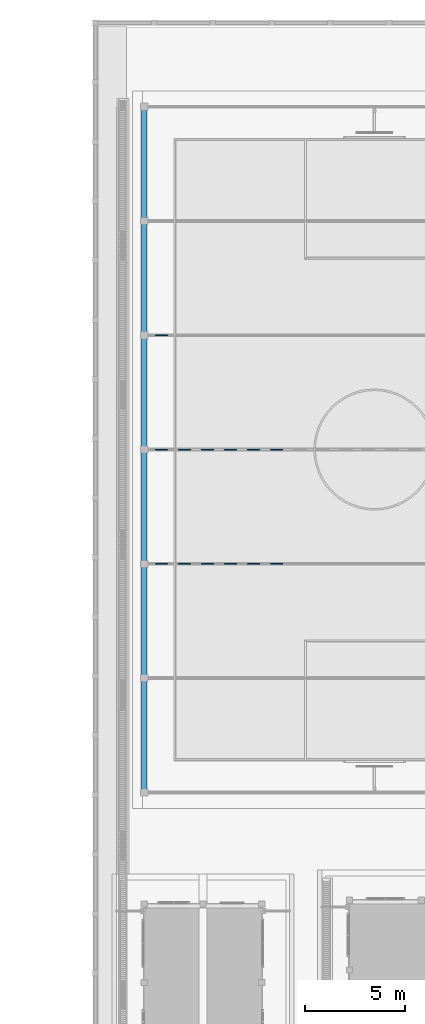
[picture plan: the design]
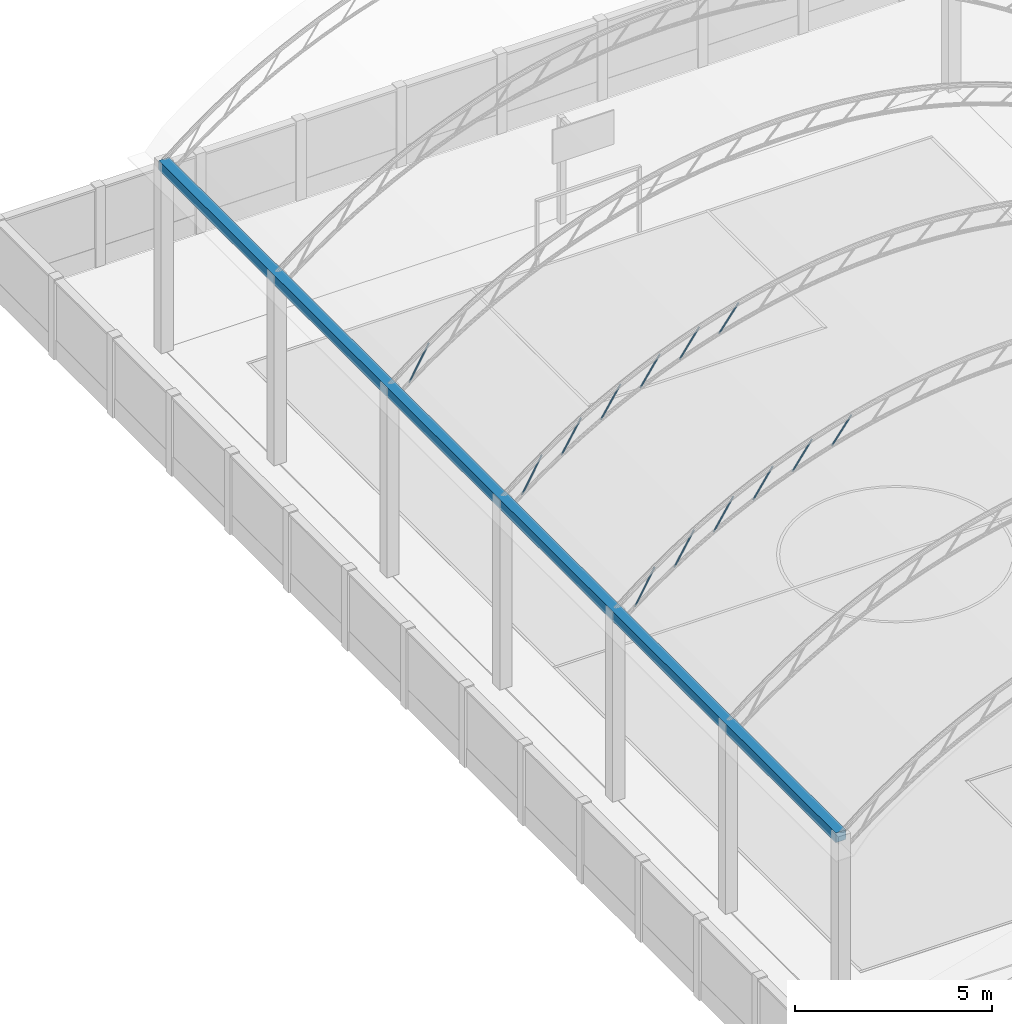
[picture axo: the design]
# One storey, part 19 of 166: 14 beams.
"""IFC2X3 building model written with IfcOpenShell, lengths in metres."""

from ifc_helpers import new_model, si_unit, origin, origin_with_axes, place, context, subcontext, project, spatial, faceted_brep, element, save


model = new_model("IFC2X3")

# Units and contexts
model_context = context("Model", 3, precision=1e-05, world=origin_with_axes())
body_context = subcontext(model_context, "Body", "Model", "MODEL_VIEW")
ifc_project = project(units=[si_unit("LENGTHUNIT", "METRE"), si_unit("AREAUNIT", "SQUARE_METRE"), si_unit("VOLUMEUNIT", "CUBIC_METRE"), si_unit("PLANEANGLEUNIT", "RADIAN")], contexts=[model_context])

# Site, building, storey
site_placement = place(None, origin_with_axes())
site = spatial("IfcSite", under=ifc_project, at=site_placement, CompositionType="ELEMENT")
building_placement = place(site_placement, origin())
building = spatial("IfcBuilding", under=site, at=building_placement, Name="de Temporal", CompositionType="ELEMENT")
storey_placement = place(building_placement, origin())
storey = spatial("IfcBuildingStorey", under=building, at=storey_placement, Name="NIVEL 1 (NPT +0.00)", CompositionType="ELEMENT", Elevation=0.0)

# Beams
beam_1_placement = place(storey_placement, origin())
element("IfcBeam", 1, at=beam_1_placement, inside=storey, Name="diag", ObjectType="Viga", context=body_context, shape_type="Brep", body=[
    faceted_brep([(4.0666, 104.0883, 5.8202), (4.6441, 104.0883, 6.8469), (4.655, 104.0917, 6.8408), (4.0775, 104.0917, 5.8141), (4.0586, 104.0792, 5.8247), (4.6361, 104.0792, 6.8514), (4.0557, 104.0667, 5.8263), (4.6332, 104.0667, 6.8531), (4.0586, 104.0542, 5.8247), (4.6361, 104.0542, 6.8514), (4.0666, 104.045, 5.8202), (4.6441, 104.045, 6.8469), (4.0775, 104.0417, 5.8141), (4.655, 104.0417, 6.8408), (4.0884, 104.045, 5.808), (4.6659, 104.045, 6.8347), (4.0964, 104.0542, 5.8035), (4.6739, 104.0542, 6.8302), (4.0993, 104.0667, 5.8018), (4.6768, 104.0667, 6.8286), (4.0964, 104.0792, 5.8035), (4.6739, 104.0792, 6.8302), (4.0884, 104.0883, 5.808), (4.6659, 104.0883, 6.8347), (4.0756, 104.0704, 5.8151), (4.0775, 104.071, 5.8141), (4.655, 104.071, 6.8408), (4.6531, 104.0704, 6.8419), (4.0743, 104.0688, 5.8159), (4.6518, 104.0688, 6.8426), (4.0738, 104.0667, 5.8162), (4.6513, 104.0667, 6.8429), (4.0743, 104.0645, 5.8159), (4.6518, 104.0645, 6.8426), (4.0756, 104.0629, 5.8151), (4.6531, 104.0629, 6.8419), (4.0775, 104.0624, 5.8141), (4.655, 104.0624, 6.8408), (4.0794, 104.0629, 5.813), (4.6569, 104.0629, 6.8398), (4.0807, 104.0645, 5.8123), (4.6582, 104.0645, 6.839), (4.0812, 104.0667, 5.812), (4.6587, 104.0667, 6.8387), (4.0807, 104.0688, 5.8123), (4.6582, 104.0688, 6.839), (4.0794, 104.0704, 5.813), (4.6569, 104.0704, 6.8398)], [[[0, 1, 2, 3]], [[4, 5, 1, 0]], [[6, 7, 5, 4]], [[8, 9, 7, 6]], [[10, 11, 9, 8]], [[12, 13, 11, 10]], [[14, 15, 13, 12]], [[16, 17, 15, 14]], [[18, 19, 17, 16]], [[20, 21, 19, 18]], [[22, 23, 21, 20]], [[3, 2, 23, 22]], [[24, 25, 26, 27]], [[28, 24, 27, 29]], [[30, 28, 29, 31]], [[32, 30, 31, 33]], [[34, 32, 33, 35]], [[36, 34, 35, 37]], [[38, 36, 37, 39]], [[40, 38, 39, 41]], [[42, 40, 41, 43]], [[44, 42, 43, 45]], [[46, 44, 45, 47]], [[25, 46, 47, 26]], [[3, 22, 46, 25]], [[7, 9, 33, 31]], [[17, 19, 43, 41]], [[23, 2, 26, 47]], [[10, 8, 32, 34]], [[20, 18, 42, 44]], [[1, 5, 29, 27]], [[13, 15, 39, 37]], [[6, 4, 28, 30]], [[16, 14, 38, 40]], [[0, 3, 25, 24]], [[9, 11, 35, 33]], [[19, 21, 45, 43]], [[12, 10, 34, 36]], [[22, 20, 44, 46]], [[5, 7, 31, 29]], [[15, 17, 41, 39]], [[2, 1, 27, 26]], [[8, 6, 30, 32]], [[18, 16, 40, 42]], [[11, 13, 37, 35]], [[21, 23, 47, 45]], [[4, 0, 24, 28]], [[14, 12, 36, 38]]]),
])
beam_2_placement = place(storey_placement, origin())
element("IfcBeam", 2, at=beam_2_placement, inside=storey, Name="diag", ObjectType="Viga", context=body_context, shape_type="Brep", body=[
    faceted_brep([(5.2218, 104.0883, 6.6398), (5.7993, 104.0883, 7.6007), (5.81, 104.0917, 7.5943), (5.2325, 104.0917, 6.6333), (5.2139, 104.0792, 6.6445), (5.7914, 104.0792, 7.6055), (5.2111, 104.0667, 6.6462), (5.7886, 104.0667, 7.6072), (5.2139, 104.0542, 6.6445), (5.7914, 104.0542, 7.6055), (5.2218, 104.045, 6.6398), (5.7993, 104.045, 7.6007), (5.2325, 104.0417, 6.6333), (5.81, 104.0417, 7.5943), (5.2432, 104.045, 6.6269), (5.8207, 104.045, 7.5879), (5.2511, 104.0542, 6.6222), (5.8286, 104.0542, 7.5832), (5.2539, 104.0667, 6.6205), (5.8314, 104.0667, 7.5814), (5.2511, 104.0792, 6.6222), (5.8286, 104.0792, 7.5832), (5.2432, 104.0883, 6.6269), (5.8207, 104.0883, 7.5879), (5.2307, 104.0704, 6.6345), (5.2325, 104.071, 6.6333), (5.81, 104.071, 7.5943), (5.8082, 104.0704, 7.5954), (5.2293, 104.0688, 6.6353), (5.8068, 104.0688, 7.5962), (5.2288, 104.0667, 6.6356), (5.8063, 104.0667, 7.5965), (5.2293, 104.0645, 6.6353), (5.8068, 104.0645, 7.5962), (5.2307, 104.0629, 6.6345), (5.8082, 104.0629, 7.5954), (5.2325, 104.0624, 6.6333), (5.81, 104.0624, 7.5943), (5.2343, 104.0629, 6.6322), (5.8118, 104.0629, 7.5932), (5.2357, 104.0645, 6.6314), (5.8132, 104.0645, 7.5924), (5.2362, 104.0667, 6.6311), (5.8137, 104.0667, 7.5921), (5.2357, 104.0688, 6.6314), (5.8132, 104.0688, 7.5924), (5.2343, 104.0704, 6.6322), (5.8118, 104.0704, 7.5932)], [[[0, 1, 2, 3]], [[4, 5, 1, 0]], [[6, 7, 5, 4]], [[8, 9, 7, 6]], [[10, 11, 9, 8]], [[12, 13, 11, 10]], [[14, 15, 13, 12]], [[16, 17, 15, 14]], [[18, 19, 17, 16]], [[20, 21, 19, 18]], [[22, 23, 21, 20]], [[3, 2, 23, 22]], [[24, 25, 26, 27]], [[28, 24, 27, 29]], [[30, 28, 29, 31]], [[32, 30, 31, 33]], [[34, 32, 33, 35]], [[36, 34, 35, 37]], [[38, 36, 37, 39]], [[40, 38, 39, 41]], [[42, 40, 41, 43]], [[44, 42, 43, 45]], [[46, 44, 45, 47]], [[25, 46, 47, 26]], [[3, 22, 46, 25]], [[7, 9, 33, 31]], [[17, 19, 43, 41]], [[23, 2, 26, 47]], [[10, 8, 32, 34]], [[20, 18, 42, 44]], [[1, 5, 29, 27]], [[13, 15, 39, 37]], [[6, 4, 28, 30]], [[16, 14, 38, 40]], [[0, 3, 25, 24]], [[9, 11, 35, 33]], [[19, 21, 45, 43]], [[12, 10, 34, 36]], [[22, 20, 44, 46]], [[5, 7, 31, 29]], [[15, 17, 41, 39]], [[2, 1, 27, 26]], [[8, 6, 30, 32]], [[18, 16, 40, 42]], [[11, 13, 37, 35]], [[21, 23, 47, 45]], [[4, 0, 24, 28]], [[14, 12, 36, 38]]]),
])
beam_3_placement = place(storey_placement, origin())
element("IfcBeam", 3, at=beam_3_placement, inside=storey, Name="diag", ObjectType="Viga", context=body_context, shape_type="Brep", body=[
    faceted_brep([(6.377, 104.0883, 7.3326), (6.9545, 104.0883, 8.2366), (6.965, 104.0917, 8.2298), (6.3875, 104.0917, 7.3259), (6.3693, 104.0792, 7.3375), (6.9468, 104.0792, 8.2415), (6.3664, 104.0667, 7.3393), (6.9439, 104.0667, 8.2433), (6.3693, 104.0542, 7.3375), (6.9468, 104.0542, 8.2415), (6.377, 104.045, 7.3326), (6.9545, 104.045, 8.2366), (6.3875, 104.0417, 7.3259), (6.965, 104.0417, 8.2298), (6.398, 104.045, 7.3191), (6.9755, 104.045, 8.2231), (6.4057, 104.0542, 7.3142), (6.9832, 104.0542, 8.2182), (6.4086, 104.0667, 7.3124), (6.9861, 104.0667, 8.2164), (6.4057, 104.0792, 7.3142), (6.9832, 104.0792, 8.2182), (6.398, 104.0883, 7.3191), (6.9755, 104.0883, 8.2231), (6.3857, 104.0704, 7.327), (6.3875, 104.071, 7.3259), (6.965, 104.071, 8.2298), (6.9632, 104.0704, 8.231), (6.3844, 104.0688, 7.3279), (6.9619, 104.0688, 8.2318), (6.3839, 104.0667, 7.3282), (6.9614, 104.0667, 8.2321), (6.3844, 104.0645, 7.3279), (6.9619, 104.0645, 8.2318), (6.3857, 104.0629, 7.327), (6.9632, 104.0629, 8.231), (6.3875, 104.0624, 7.3259), (6.965, 104.0624, 8.2298), (6.3893, 104.0629, 7.3247), (6.9668, 104.0629, 8.2287), (6.3906, 104.0645, 7.3239), (6.9681, 104.0645, 8.2278), (6.3911, 104.0667, 7.3235), (6.9686, 104.0667, 8.2275), (6.3906, 104.0688, 7.3239), (6.9681, 104.0688, 8.2278), (6.3893, 104.0704, 7.3247), (6.9668, 104.0704, 8.2287)], [[[0, 1, 2, 3]], [[4, 5, 1, 0]], [[6, 7, 5, 4]], [[8, 9, 7, 6]], [[10, 11, 9, 8]], [[12, 13, 11, 10]], [[14, 15, 13, 12]], [[16, 17, 15, 14]], [[18, 19, 17, 16]], [[20, 21, 19, 18]], [[22, 23, 21, 20]], [[3, 2, 23, 22]], [[24, 25, 26, 27]], [[28, 24, 27, 29]], [[30, 28, 29, 31]], [[32, 30, 31, 33]], [[34, 32, 33, 35]], [[36, 34, 35, 37]], [[38, 36, 37, 39]], [[40, 38, 39, 41]], [[42, 40, 41, 43]], [[44, 42, 43, 45]], [[46, 44, 45, 47]], [[25, 46, 47, 26]], [[3, 22, 46, 25]], [[7, 9, 33, 31]], [[17, 19, 43, 41]], [[23, 2, 26, 47]], [[10, 8, 32, 34]], [[20, 18, 42, 44]], [[1, 5, 29, 27]], [[13, 15, 39, 37]], [[6, 4, 28, 30]], [[16, 14, 38, 40]], [[0, 3, 25, 24]], [[9, 11, 35, 33]], [[19, 21, 45, 43]], [[12, 10, 34, 36]], [[22, 20, 44, 46]], [[5, 7, 31, 29]], [[15, 17, 41, 39]], [[2, 1, 27, 26]], [[8, 6, 30, 32]], [[18, 16, 40, 42]], [[11, 13, 37, 35]], [[21, 23, 47, 45]], [[4, 0, 24, 28]], [[14, 12, 36, 38]]]),
])
beam_4_placement = place(storey_placement, origin())
element("IfcBeam", 4, at=beam_4_placement, inside=storey, Name="diag", ObjectType="Viga", context=body_context, shape_type="Brep", body=[
    faceted_brep([(7.5321, 104.0883, 7.9148), (8.1096, 104.0883, 8.7679), (8.12, 104.0917, 8.7609), (7.5425, 104.0917, 7.9077), (7.5246, 104.0792, 7.9199), (8.1021, 104.0792, 8.7731), (7.5218, 104.0667, 7.9218), (8.0993, 104.0667, 8.7749), (7.5246, 104.0542, 7.9199), (8.1021, 104.0542, 8.7731), (7.5321, 104.045, 7.9148), (8.1096, 104.045, 8.7679), (7.5425, 104.0417, 7.9077), (8.12, 104.0417, 8.7609), (7.5529, 104.045, 7.9007), (8.1304, 104.045, 8.7539), (7.5604, 104.0542, 7.8956), (8.1379, 104.0542, 8.7488), (7.5632, 104.0667, 7.8937), (8.1407, 104.0667, 8.7469), (7.5604, 104.0792, 7.8956), (8.1379, 104.0792, 8.7488), (7.5529, 104.0883, 7.9007), (8.1304, 104.0883, 8.7539), (7.5407, 104.0704, 7.9089), (7.5425, 104.071, 7.9077), (8.12, 104.071, 8.7609), (8.1182, 104.0704, 8.7621), (7.5394, 104.0688, 7.9098), (8.1169, 104.0688, 8.763), (7.5389, 104.0667, 7.9102), (8.1164, 104.0667, 8.7633), (7.5394, 104.0645, 7.9098), (8.1169, 104.0645, 8.763), (7.5407, 104.0629, 7.9089), (8.1182, 104.0629, 8.7621), (7.5425, 104.0624, 7.9077), (8.12, 104.0624, 8.7609), (7.5443, 104.0629, 7.9065), (8.1218, 104.0629, 8.7597), (7.5456, 104.0645, 7.9057), (8.1231, 104.0645, 8.7588), (7.5461, 104.0667, 7.9053), (8.1236, 104.0667, 8.7585), (7.5456, 104.0688, 7.9057), (8.1231, 104.0688, 8.7588), (7.5443, 104.0704, 7.9065), (8.1218, 104.0704, 8.7597)], [[[0, 1, 2, 3]], [[4, 5, 1, 0]], [[6, 7, 5, 4]], [[8, 9, 7, 6]], [[10, 11, 9, 8]], [[12, 13, 11, 10]], [[14, 15, 13, 12]], [[16, 17, 15, 14]], [[18, 19, 17, 16]], [[20, 21, 19, 18]], [[22, 23, 21, 20]], [[3, 2, 23, 22]], [[24, 25, 26, 27]], [[28, 24, 27, 29]], [[30, 28, 29, 31]], [[32, 30, 31, 33]], [[34, 32, 33, 35]], [[36, 34, 35, 37]], [[38, 36, 37, 39]], [[40, 38, 39, 41]], [[42, 40, 41, 43]], [[44, 42, 43, 45]], [[46, 44, 45, 47]], [[25, 46, 47, 26]], [[3, 22, 46, 25]], [[7, 9, 33, 31]], [[17, 19, 43, 41]], [[23, 2, 26, 47]], [[10, 8, 32, 34]], [[20, 18, 42, 44]], [[1, 5, 29, 27]], [[13, 15, 39, 37]], [[6, 4, 28, 30]], [[16, 14, 38, 40]], [[0, 3, 25, 24]], [[9, 11, 35, 33]], [[19, 21, 45, 43]], [[12, 10, 34, 36]], [[22, 20, 44, 46]], [[5, 7, 31, 29]], [[15, 17, 41, 39]], [[2, 1, 27, 26]], [[8, 6, 30, 32]], [[18, 16, 40, 42]], [[11, 13, 37, 35]], [[21, 23, 47, 45]], [[4, 0, 24, 28]], [[14, 12, 36, 38]]]),
])
beam_5_placement = place(storey_placement, origin())
element("IfcBeam", 5, at=beam_5_placement, inside=storey, Name="diag", ObjectType="Viga", context=body_context, shape_type="Brep", body=[
    faceted_brep([(8.6873, 104.0883, 8.3978), (9.2648, 104.0883, 9.2047), (9.275, 104.0917, 9.1974), (8.6975, 104.0917, 8.3905), (8.6799, 104.0792, 8.4031), (9.2574, 104.0792, 9.21), (8.6772, 104.0667, 8.405), (9.2547, 104.0667, 9.2119), (8.6799, 104.0542, 8.4031), (9.2574, 104.0542, 9.21), (8.6873, 104.045, 8.3978), (9.2648, 104.045, 9.2047), (8.6975, 104.0417, 8.3905), (9.275, 104.0417, 9.1974), (8.7077, 104.045, 8.3832), (9.2852, 104.045, 9.1901), (8.7151, 104.0542, 8.3779), (9.2926, 104.0542, 9.1848), (8.7178, 104.0667, 8.3759), (9.2953, 104.0667, 9.1828), (8.7151, 104.0792, 8.3779), (9.2926, 104.0792, 9.1848), (8.7077, 104.0883, 8.3832), (9.2852, 104.0883, 9.1901), (8.6958, 104.0704, 8.3917), (8.6975, 104.071, 8.3905), (9.275, 104.071, 9.1974), (9.2733, 104.0704, 9.1986), (8.6945, 104.0688, 8.3927), (9.272, 104.0688, 9.1996), (8.694, 104.0667, 8.393), (9.2715, 104.0667, 9.1999), (8.6945, 104.0645, 8.3927), (9.272, 104.0645, 9.1996), (8.6958, 104.0629, 8.3917), (9.2733, 104.0629, 9.1986), (8.6975, 104.0624, 8.3905), (9.275, 104.0624, 9.1974), (8.6992, 104.0629, 8.3892), (9.2767, 104.0629, 9.1961), (8.7005, 104.0645, 8.3883), (9.278, 104.0645, 9.1952), (8.701, 104.0667, 8.388), (9.2785, 104.0667, 9.1949), (8.7005, 104.0688, 8.3883), (9.278, 104.0688, 9.1952), (8.6992, 104.0704, 8.3892), (9.2767, 104.0704, 9.1961)], [[[0, 1, 2, 3]], [[4, 5, 1, 0]], [[6, 7, 5, 4]], [[8, 9, 7, 6]], [[10, 11, 9, 8]], [[12, 13, 11, 10]], [[14, 15, 13, 12]], [[16, 17, 15, 14]], [[18, 19, 17, 16]], [[20, 21, 19, 18]], [[22, 23, 21, 20]], [[3, 2, 23, 22]], [[24, 25, 26, 27]], [[28, 24, 27, 29]], [[30, 28, 29, 31]], [[32, 30, 31, 33]], [[34, 32, 33, 35]], [[36, 34, 35, 37]], [[38, 36, 37, 39]], [[40, 38, 39, 41]], [[42, 40, 41, 43]], [[44, 42, 43, 45]], [[46, 44, 45, 47]], [[25, 46, 47, 26]], [[3, 22, 46, 25]], [[7, 9, 33, 31]], [[17, 19, 43, 41]], [[23, 2, 26, 47]], [[10, 8, 32, 34]], [[20, 18, 42, 44]], [[1, 5, 29, 27]], [[13, 15, 39, 37]], [[6, 4, 28, 30]], [[16, 14, 38, 40]], [[0, 3, 25, 24]], [[9, 11, 35, 33]], [[19, 21, 45, 43]], [[12, 10, 34, 36]], [[22, 20, 44, 46]], [[5, 7, 31, 29]], [[15, 17, 41, 39]], [[2, 1, 27, 26]], [[8, 6, 30, 32]], [[18, 16, 40, 42]], [[11, 13, 37, 35]], [[21, 23, 47, 45]], [[4, 0, 24, 28]], [[14, 12, 36, 38]]]),
])
beam_6_placement = place(storey_placement, origin())
element("IfcBeam", 6, at=beam_6_placement, inside=storey, Name="diag", ObjectType="Viga", context=body_context, shape_type="Brep", body=[
    faceted_brep([(9.8425, 104.0883, 8.79), (10.42, 104.0883, 9.5539), (10.43, 104.0917, 9.5463), (9.8525, 104.0917, 8.7824), (9.8352, 104.0792, 8.7955), (10.4127, 104.0792, 9.5594), (9.8326, 104.0667, 8.7975), (10.4101, 104.0667, 9.5614), (9.8352, 104.0542, 8.7955), (10.4127, 104.0542, 9.5594), (9.8425, 104.045, 8.79), (10.42, 104.045, 9.5539), (9.8525, 104.0417, 8.7824), (10.43, 104.0417, 9.5463), (9.8625, 104.045, 8.7749), (10.44, 104.045, 9.5388), (9.8698, 104.0542, 8.7694), (10.4473, 104.0542, 9.5333), (9.8724, 104.0667, 8.7674), (10.4499, 104.0667, 9.5313), (9.8698, 104.0792, 8.7694), (10.4473, 104.0792, 9.5333), (9.8625, 104.0883, 8.7749), (10.44, 104.0883, 9.5388), (9.8508, 104.0704, 8.7837), (9.8525, 104.071, 8.7824), (10.43, 104.071, 9.5463), (10.4283, 104.0704, 9.5476), (9.8495, 104.0688, 8.7847), (10.427, 104.0688, 9.5486), (9.8491, 104.0667, 8.785), (10.4266, 104.0667, 9.5489), (9.8495, 104.0645, 8.7847), (10.427, 104.0645, 9.5486), (9.8508, 104.0629, 8.7837), (10.4283, 104.0629, 9.5476), (9.8525, 104.0624, 8.7824), (10.43, 104.0624, 9.5463), (9.8542, 104.0629, 8.7812), (10.4317, 104.0629, 9.5451), (9.8555, 104.0645, 8.7802), (10.433, 104.0645, 9.5441), (9.8559, 104.0667, 8.7799), (10.4334, 104.0667, 9.5438), (9.8555, 104.0688, 8.7802), (10.433, 104.0688, 9.5441), (9.8542, 104.0704, 8.7812), (10.4317, 104.0704, 9.5451)], [[[0, 1, 2, 3]], [[4, 5, 1, 0]], [[6, 7, 5, 4]], [[8, 9, 7, 6]], [[10, 11, 9, 8]], [[12, 13, 11, 10]], [[14, 15, 13, 12]], [[16, 17, 15, 14]], [[18, 19, 17, 16]], [[20, 21, 19, 18]], [[22, 23, 21, 20]], [[3, 2, 23, 22]], [[24, 25, 26, 27]], [[28, 24, 27, 29]], [[30, 28, 29, 31]], [[32, 30, 31, 33]], [[34, 32, 33, 35]], [[36, 34, 35, 37]], [[38, 36, 37, 39]], [[40, 38, 39, 41]], [[42, 40, 41, 43]], [[44, 42, 43, 45]], [[46, 44, 45, 47]], [[25, 46, 47, 26]], [[3, 22, 46, 25]], [[7, 9, 33, 31]], [[17, 19, 43, 41]], [[23, 2, 26, 47]], [[10, 8, 32, 34]], [[20, 18, 42, 44]], [[1, 5, 29, 27]], [[13, 15, 39, 37]], [[6, 4, 28, 30]], [[16, 14, 38, 40]], [[0, 3, 25, 24]], [[9, 11, 35, 33]], [[19, 21, 45, 43]], [[12, 10, 34, 36]], [[22, 20, 44, 46]], [[5, 7, 31, 29]], [[15, 17, 41, 39]], [[2, 1, 27, 26]], [[8, 6, 30, 32]], [[18, 16, 40, 42]], [[11, 13, 37, 35]], [[21, 23, 47, 45]], [[4, 0, 24, 28]], [[14, 12, 36, 38]]]),
])
beam_7_placement = place(storey_placement, origin())
element("IfcBeam", 7, at=beam_7_placement, inside=storey, Name="diag", ObjectType="Viga", context=body_context, shape_type="Brep", body=[
    faceted_brep([(4.0666, 109.8217, 5.8202), (4.6441, 109.8217, 6.8469), (4.655, 109.825, 6.8408), (4.0775, 109.825, 5.8141), (4.0586, 109.8125, 5.8247), (4.6361, 109.8125, 6.8514), (4.0557, 109.8, 5.8263), (4.6332, 109.8, 6.8531), (4.0586, 109.7875, 5.8247), (4.6361, 109.7875, 6.8514), (4.0666, 109.7784, 5.8202), (4.6441, 109.7784, 6.8469), (4.0775, 109.775, 5.8141), (4.655, 109.775, 6.8408), (4.0884, 109.7784, 5.808), (4.6659, 109.7784, 6.8347), (4.0964, 109.7875, 5.8035), (4.6739, 109.7875, 6.8302), (4.0993, 109.8, 5.8018), (4.6768, 109.8, 6.8286), (4.0964, 109.8125, 5.8035), (4.6739, 109.8125, 6.8302), (4.0884, 109.8217, 5.808), (4.6659, 109.8217, 6.8347), (4.0756, 109.8037, 5.8151), (4.0775, 109.8043, 5.8141), (4.655, 109.8043, 6.8408), (4.6531, 109.8037, 6.8419), (4.0743, 109.8021, 5.8159), (4.6518, 109.8021, 6.8426), (4.0738, 109.8, 5.8162), (4.6513, 109.8, 6.8429), (4.0743, 109.7979, 5.8159), (4.6518, 109.7979, 6.8426), (4.0756, 109.7963, 5.8151), (4.6531, 109.7963, 6.8419), (4.0775, 109.7957, 5.8141), (4.655, 109.7957, 6.8408), (4.0794, 109.7963, 5.813), (4.6569, 109.7963, 6.8398), (4.0807, 109.7979, 5.8123), (4.6582, 109.7979, 6.839), (4.0812, 109.8, 5.812), (4.6587, 109.8, 6.8387), (4.0807, 109.8021, 5.8123), (4.6582, 109.8021, 6.839), (4.0794, 109.8037, 5.813), (4.6569, 109.8037, 6.8398)], [[[0, 1, 2, 3]], [[4, 5, 1, 0]], [[6, 7, 5, 4]], [[8, 9, 7, 6]], [[10, 11, 9, 8]], [[12, 13, 11, 10]], [[14, 15, 13, 12]], [[16, 17, 15, 14]], [[18, 19, 17, 16]], [[20, 21, 19, 18]], [[22, 23, 21, 20]], [[3, 2, 23, 22]], [[24, 25, 26, 27]], [[28, 24, 27, 29]], [[30, 28, 29, 31]], [[32, 30, 31, 33]], [[34, 32, 33, 35]], [[36, 34, 35, 37]], [[38, 36, 37, 39]], [[40, 38, 39, 41]], [[42, 40, 41, 43]], [[44, 42, 43, 45]], [[46, 44, 45, 47]], [[25, 46, 47, 26]], [[12, 10, 34, 36]], [[22, 20, 44, 46]], [[5, 7, 31, 29]], [[15, 17, 41, 39]], [[2, 1, 27, 26]], [[8, 6, 30, 32]], [[18, 16, 40, 42]], [[11, 13, 37, 35]], [[21, 23, 47, 45]], [[4, 0, 24, 28]], [[14, 12, 36, 38]], [[3, 22, 46, 25]], [[7, 9, 33, 31]], [[17, 19, 43, 41]], [[23, 2, 26, 47]], [[10, 8, 32, 34]], [[20, 18, 42, 44]], [[1, 5, 29, 27]], [[13, 15, 39, 37]], [[6, 4, 28, 30]], [[16, 14, 38, 40]], [[0, 3, 25, 24]], [[9, 11, 35, 33]], [[19, 21, 45, 43]]]),
])
beam_8_placement = place(storey_placement, origin())
element("IfcBeam", 8, at=beam_8_placement, inside=storey, Name="diag", ObjectType="Viga", context=body_context, shape_type="Brep", body=[
    faceted_brep([(5.2218, 109.8217, 6.6398), (5.7993, 109.8217, 7.6007), (5.81, 109.825, 7.5943), (5.2325, 109.825, 6.6333), (5.2139, 109.8125, 6.6445), (5.7914, 109.8125, 7.6055), (5.2111, 109.8, 6.6462), (5.7886, 109.8, 7.6072), (5.2139, 109.7875, 6.6445), (5.7914, 109.7875, 7.6055), (5.2218, 109.7784, 6.6398), (5.7993, 109.7784, 7.6007), (5.2325, 109.775, 6.6333), (5.81, 109.775, 7.5943), (5.2432, 109.7784, 6.6269), (5.8207, 109.7784, 7.5879), (5.2511, 109.7875, 6.6222), (5.8286, 109.7875, 7.5832), (5.2539, 109.8, 6.6205), (5.8314, 109.8, 7.5814), (5.2511, 109.8125, 6.6222), (5.8286, 109.8125, 7.5832), (5.2432, 109.8217, 6.6269), (5.8207, 109.8217, 7.5879), (5.2307, 109.8037, 6.6345), (5.2325, 109.8043, 6.6333), (5.81, 109.8043, 7.5943), (5.8082, 109.8037, 7.5954), (5.2293, 109.8021, 6.6353), (5.8068, 109.8021, 7.5962), (5.2288, 109.8, 6.6356), (5.8063, 109.8, 7.5965), (5.2293, 109.7979, 6.6353), (5.8068, 109.7979, 7.5962), (5.2307, 109.7963, 6.6345), (5.8082, 109.7963, 7.5954), (5.2325, 109.7957, 6.6333), (5.81, 109.7957, 7.5943), (5.2343, 109.7963, 6.6322), (5.8118, 109.7963, 7.5932), (5.2357, 109.7979, 6.6314), (5.8132, 109.7979, 7.5924), (5.2362, 109.8, 6.6311), (5.8137, 109.8, 7.5921), (5.2357, 109.8021, 6.6314), (5.8132, 109.8021, 7.5924), (5.2343, 109.8037, 6.6322), (5.8118, 109.8037, 7.5932)], [[[0, 1, 2, 3]], [[4, 5, 1, 0]], [[6, 7, 5, 4]], [[8, 9, 7, 6]], [[10, 11, 9, 8]], [[12, 13, 11, 10]], [[14, 15, 13, 12]], [[16, 17, 15, 14]], [[18, 19, 17, 16]], [[20, 21, 19, 18]], [[22, 23, 21, 20]], [[3, 2, 23, 22]], [[24, 25, 26, 27]], [[28, 24, 27, 29]], [[30, 28, 29, 31]], [[32, 30, 31, 33]], [[34, 32, 33, 35]], [[36, 34, 35, 37]], [[38, 36, 37, 39]], [[40, 38, 39, 41]], [[42, 40, 41, 43]], [[44, 42, 43, 45]], [[46, 44, 45, 47]], [[25, 46, 47, 26]], [[12, 10, 34, 36]], [[22, 20, 44, 46]], [[5, 7, 31, 29]], [[15, 17, 41, 39]], [[2, 1, 27, 26]], [[8, 6, 30, 32]], [[18, 16, 40, 42]], [[11, 13, 37, 35]], [[21, 23, 47, 45]], [[4, 0, 24, 28]], [[14, 12, 36, 38]], [[3, 22, 46, 25]], [[7, 9, 33, 31]], [[17, 19, 43, 41]], [[23, 2, 26, 47]], [[10, 8, 32, 34]], [[20, 18, 42, 44]], [[1, 5, 29, 27]], [[13, 15, 39, 37]], [[6, 4, 28, 30]], [[16, 14, 38, 40]], [[0, 3, 25, 24]], [[9, 11, 35, 33]], [[19, 21, 45, 43]]]),
])
beam_9_placement = place(storey_placement, origin())
element("IfcBeam", 9, at=beam_9_placement, inside=storey, Name="diag", ObjectType="Viga", context=body_context, shape_type="Brep", body=[
    faceted_brep([(6.377, 109.8217, 7.3326), (6.9545, 109.8217, 8.2366), (6.965, 109.825, 8.2298), (6.3875, 109.825, 7.3259), (6.3693, 109.8125, 7.3375), (6.9468, 109.8125, 8.2415), (6.3664, 109.8, 7.3393), (6.9439, 109.8, 8.2433), (6.3693, 109.7875, 7.3375), (6.9468, 109.7875, 8.2415), (6.377, 109.7784, 7.3326), (6.9545, 109.7784, 8.2366), (6.3875, 109.775, 7.3259), (6.965, 109.775, 8.2298), (6.398, 109.7784, 7.3191), (6.9755, 109.7784, 8.2231), (6.4057, 109.7875, 7.3142), (6.9832, 109.7875, 8.2182), (6.4086, 109.8, 7.3124), (6.9861, 109.8, 8.2164), (6.4057, 109.8125, 7.3142), (6.9832, 109.8125, 8.2182), (6.398, 109.8217, 7.3191), (6.9755, 109.8217, 8.2231), (6.3857, 109.8037, 7.327), (6.3875, 109.8043, 7.3259), (6.965, 109.8043, 8.2298), (6.9632, 109.8037, 8.231), (6.3844, 109.8021, 7.3279), (6.9619, 109.8021, 8.2318), (6.3839, 109.8, 7.3282), (6.9614, 109.8, 8.2321), (6.3844, 109.7979, 7.3279), (6.9619, 109.7979, 8.2318), (6.3857, 109.7963, 7.327), (6.9632, 109.7963, 8.231), (6.3875, 109.7957, 7.3259), (6.965, 109.7957, 8.2298), (6.3893, 109.7963, 7.3247), (6.9668, 109.7963, 8.2287), (6.3906, 109.7979, 7.3239), (6.9681, 109.7979, 8.2278), (6.3911, 109.8, 7.3235), (6.9686, 109.8, 8.2275), (6.3906, 109.8021, 7.3239), (6.9681, 109.8021, 8.2278), (6.3893, 109.8037, 7.3247), (6.9668, 109.8037, 8.2287)], [[[0, 1, 2, 3]], [[4, 5, 1, 0]], [[6, 7, 5, 4]], [[8, 9, 7, 6]], [[10, 11, 9, 8]], [[12, 13, 11, 10]], [[14, 15, 13, 12]], [[16, 17, 15, 14]], [[18, 19, 17, 16]], [[20, 21, 19, 18]], [[22, 23, 21, 20]], [[3, 2, 23, 22]], [[24, 25, 26, 27]], [[28, 24, 27, 29]], [[30, 28, 29, 31]], [[32, 30, 31, 33]], [[34, 32, 33, 35]], [[36, 34, 35, 37]], [[38, 36, 37, 39]], [[40, 38, 39, 41]], [[42, 40, 41, 43]], [[44, 42, 43, 45]], [[46, 44, 45, 47]], [[25, 46, 47, 26]], [[11, 13, 37, 35]], [[21, 23, 47, 45]], [[4, 0, 24, 28]], [[14, 12, 36, 38]], [[3, 22, 46, 25]], [[7, 9, 33, 31]], [[17, 19, 43, 41]], [[23, 2, 26, 47]], [[10, 8, 32, 34]], [[20, 18, 42, 44]], [[1, 5, 29, 27]], [[13, 15, 39, 37]], [[6, 4, 28, 30]], [[16, 14, 38, 40]], [[0, 3, 25, 24]], [[9, 11, 35, 33]], [[19, 21, 45, 43]], [[12, 10, 34, 36]], [[22, 20, 44, 46]], [[5, 7, 31, 29]], [[15, 17, 41, 39]], [[2, 1, 27, 26]], [[8, 6, 30, 32]], [[18, 16, 40, 42]]]),
])
beam_10_placement = place(storey_placement, origin())
element("IfcBeam", 10, at=beam_10_placement, inside=storey, Name="diag", ObjectType="Viga", context=body_context, shape_type="Brep", body=[
    faceted_brep([(7.5321, 109.8217, 7.9148), (8.1096, 109.8217, 8.7679), (8.12, 109.825, 8.7609), (7.5425, 109.825, 7.9077), (7.5246, 109.8125, 7.9199), (8.1021, 109.8125, 8.7731), (7.5218, 109.8, 7.9218), (8.0993, 109.8, 8.7749), (7.5246, 109.7875, 7.9199), (8.1021, 109.7875, 8.7731), (7.5321, 109.7784, 7.9148), (8.1096, 109.7784, 8.7679), (7.5425, 109.775, 7.9077), (8.12, 109.775, 8.7609), (7.5529, 109.7784, 7.9007), (8.1304, 109.7784, 8.7539), (7.5604, 109.7875, 7.8956), (8.1379, 109.7875, 8.7488), (7.5632, 109.8, 7.8937), (8.1407, 109.8, 8.7469), (7.5604, 109.8125, 7.8956), (8.1379, 109.8125, 8.7488), (7.5529, 109.8217, 7.9007), (8.1304, 109.8217, 8.7539), (7.5407, 109.8037, 7.9089), (7.5425, 109.8043, 7.9077), (8.12, 109.8043, 8.7609), (8.1182, 109.8037, 8.7621), (7.5394, 109.8021, 7.9098), (8.1169, 109.8021, 8.763), (7.5389, 109.8, 7.9102), (8.1164, 109.8, 8.7633), (7.5394, 109.7979, 7.9098), (8.1169, 109.7979, 8.763), (7.5407, 109.7963, 7.9089), (8.1182, 109.7963, 8.7621), (7.5425, 109.7957, 7.9077), (8.12, 109.7957, 8.7609), (7.5443, 109.7963, 7.9065), (8.1218, 109.7963, 8.7597), (7.5456, 109.7979, 7.9057), (8.1231, 109.7979, 8.7588), (7.5461, 109.8, 7.9053), (8.1236, 109.8, 8.7585), (7.5456, 109.8021, 7.9057), (8.1231, 109.8021, 8.7588), (7.5443, 109.8037, 7.9065), (8.1218, 109.8037, 8.7597)], [[[0, 1, 2, 3]], [[4, 5, 1, 0]], [[6, 7, 5, 4]], [[8, 9, 7, 6]], [[10, 11, 9, 8]], [[12, 13, 11, 10]], [[14, 15, 13, 12]], [[16, 17, 15, 14]], [[18, 19, 17, 16]], [[20, 21, 19, 18]], [[22, 23, 21, 20]], [[3, 2, 23, 22]], [[24, 25, 26, 27]], [[28, 24, 27, 29]], [[30, 28, 29, 31]], [[32, 30, 31, 33]], [[34, 32, 33, 35]], [[36, 34, 35, 37]], [[38, 36, 37, 39]], [[40, 38, 39, 41]], [[42, 40, 41, 43]], [[44, 42, 43, 45]], [[46, 44, 45, 47]], [[25, 46, 47, 26]], [[11, 13, 37, 35]], [[21, 23, 47, 45]], [[4, 0, 24, 28]], [[14, 12, 36, 38]], [[3, 22, 46, 25]], [[7, 9, 33, 31]], [[17, 19, 43, 41]], [[23, 2, 26, 47]], [[10, 8, 32, 34]], [[20, 18, 42, 44]], [[1, 5, 29, 27]], [[13, 15, 39, 37]], [[6, 4, 28, 30]], [[16, 14, 38, 40]], [[0, 3, 25, 24]], [[9, 11, 35, 33]], [[19, 21, 45, 43]], [[12, 10, 34, 36]], [[22, 20, 44, 46]], [[5, 7, 31, 29]], [[15, 17, 41, 39]], [[2, 1, 27, 26]], [[8, 6, 30, 32]], [[18, 16, 40, 42]]]),
])
beam_11_placement = place(storey_placement, origin())
element("IfcBeam", 11, at=beam_11_placement, inside=storey, Name="diag", ObjectType="Viga", context=body_context, shape_type="Brep", body=[
    faceted_brep([(8.6873, 109.8217, 8.3978), (9.2648, 109.8217, 9.2047), (9.275, 109.825, 9.1974), (8.6975, 109.825, 8.3905), (8.6799, 109.8125, 8.4031), (9.2574, 109.8125, 9.21), (8.6772, 109.8, 8.405), (9.2547, 109.8, 9.2119), (8.6799, 109.7875, 8.4031), (9.2574, 109.7875, 9.21), (8.6873, 109.7784, 8.3978), (9.2648, 109.7784, 9.2047), (8.6975, 109.775, 8.3905), (9.275, 109.775, 9.1974), (8.7077, 109.7784, 8.3832), (9.2852, 109.7784, 9.1901), (8.7151, 109.7875, 8.3779), (9.2926, 109.7875, 9.1848), (8.7178, 109.8, 8.3759), (9.2953, 109.8, 9.1828), (8.7151, 109.8125, 8.3779), (9.2926, 109.8125, 9.1848), (8.7077, 109.8217, 8.3832), (9.2852, 109.8217, 9.1901), (8.6958, 109.8037, 8.3917), (8.6975, 109.8043, 8.3905), (9.275, 109.8043, 9.1974), (9.2733, 109.8037, 9.1986), (8.6945, 109.8021, 8.3927), (9.272, 109.8021, 9.1996), (8.694, 109.8, 8.393), (9.2715, 109.8, 9.1999), (8.6945, 109.7979, 8.3927), (9.272, 109.7979, 9.1996), (8.6958, 109.7963, 8.3917), (9.2733, 109.7963, 9.1986), (8.6975, 109.7957, 8.3905), (9.275, 109.7957, 9.1974), (8.6992, 109.7963, 8.3892), (9.2767, 109.7963, 9.1961), (8.7005, 109.7979, 8.3883), (9.278, 109.7979, 9.1952), (8.701, 109.8, 8.388), (9.2785, 109.8, 9.1949), (8.7005, 109.8021, 8.3883), (9.278, 109.8021, 9.1952), (8.6992, 109.8037, 8.3892), (9.2767, 109.8037, 9.1961)], [[[0, 1, 2, 3]], [[4, 5, 1, 0]], [[6, 7, 5, 4]], [[8, 9, 7, 6]], [[10, 11, 9, 8]], [[12, 13, 11, 10]], [[14, 15, 13, 12]], [[16, 17, 15, 14]], [[18, 19, 17, 16]], [[20, 21, 19, 18]], [[22, 23, 21, 20]], [[3, 2, 23, 22]], [[24, 25, 26, 27]], [[28, 24, 27, 29]], [[30, 28, 29, 31]], [[32, 30, 31, 33]], [[34, 32, 33, 35]], [[36, 34, 35, 37]], [[38, 36, 37, 39]], [[40, 38, 39, 41]], [[42, 40, 41, 43]], [[44, 42, 43, 45]], [[46, 44, 45, 47]], [[25, 46, 47, 26]], [[11, 13, 37, 35]], [[21, 23, 47, 45]], [[4, 0, 24, 28]], [[14, 12, 36, 38]], [[3, 22, 46, 25]], [[7, 9, 33, 31]], [[17, 19, 43, 41]], [[23, 2, 26, 47]], [[10, 8, 32, 34]], [[20, 18, 42, 44]], [[1, 5, 29, 27]], [[13, 15, 39, 37]], [[6, 4, 28, 30]], [[16, 14, 38, 40]], [[0, 3, 25, 24]], [[9, 11, 35, 33]], [[19, 21, 45, 43]], [[12, 10, 34, 36]], [[22, 20, 44, 46]], [[5, 7, 31, 29]], [[15, 17, 41, 39]], [[2, 1, 27, 26]], [[8, 6, 30, 32]], [[18, 16, 40, 42]]]),
])
beam_12_placement = place(storey_placement, origin())
element("IfcBeam", 12, at=beam_12_placement, inside=storey, Name="diag", ObjectType="Viga", context=body_context, shape_type="Brep", body=[
    faceted_brep([(9.8425, 109.8217, 8.79), (10.42, 109.8217, 9.5539), (10.43, 109.825, 9.5463), (9.8525, 109.825, 8.7824), (9.8352, 109.8125, 8.7955), (10.4127, 109.8125, 9.5594), (9.8326, 109.8, 8.7975), (10.4101, 109.8, 9.5614), (9.8352, 109.7875, 8.7955), (10.4127, 109.7875, 9.5594), (9.8425, 109.7784, 8.79), (10.42, 109.7784, 9.5539), (9.8525, 109.775, 8.7824), (10.43, 109.775, 9.5463), (9.8625, 109.7784, 8.7749), (10.44, 109.7784, 9.5388), (9.8698, 109.7875, 8.7694), (10.4473, 109.7875, 9.5333), (9.8724, 109.8, 8.7674), (10.4499, 109.8, 9.5313), (9.8698, 109.8125, 8.7694), (10.4473, 109.8125, 9.5333), (9.8625, 109.8217, 8.7749), (10.44, 109.8217, 9.5388), (9.8508, 109.8037, 8.7837), (9.8525, 109.8043, 8.7824), (10.43, 109.8043, 9.5463), (10.4283, 109.8037, 9.5476), (9.8495, 109.8021, 8.7847), (10.427, 109.8021, 9.5486), (9.8491, 109.8, 8.785), (10.4266, 109.8, 9.5489), (9.8495, 109.7979, 8.7847), (10.427, 109.7979, 9.5486), (9.8508, 109.7963, 8.7837), (10.4283, 109.7963, 9.5476), (9.8525, 109.7957, 8.7824), (10.43, 109.7957, 9.5463), (9.8542, 109.7963, 8.7812), (10.4317, 109.7963, 9.5451), (9.8555, 109.7979, 8.7802), (10.433, 109.7979, 9.5441), (9.8559, 109.8, 8.7799), (10.4334, 109.8, 9.5438), (9.8555, 109.8021, 8.7802), (10.433, 109.8021, 9.5441), (9.8542, 109.8037, 8.7812), (10.4317, 109.8037, 9.5451)], [[[0, 1, 2, 3]], [[4, 5, 1, 0]], [[6, 7, 5, 4]], [[8, 9, 7, 6]], [[10, 11, 9, 8]], [[12, 13, 11, 10]], [[14, 15, 13, 12]], [[16, 17, 15, 14]], [[18, 19, 17, 16]], [[20, 21, 19, 18]], [[22, 23, 21, 20]], [[3, 2, 23, 22]], [[24, 25, 26, 27]], [[28, 24, 27, 29]], [[30, 28, 29, 31]], [[32, 30, 31, 33]], [[34, 32, 33, 35]], [[36, 34, 35, 37]], [[38, 36, 37, 39]], [[40, 38, 39, 41]], [[42, 40, 41, 43]], [[44, 42, 43, 45]], [[46, 44, 45, 47]], [[25, 46, 47, 26]], [[11, 13, 37, 35]], [[21, 23, 47, 45]], [[4, 0, 24, 28]], [[14, 12, 36, 38]], [[3, 22, 46, 25]], [[7, 9, 33, 31]], [[17, 19, 43, 41]], [[23, 2, 26, 47]], [[10, 8, 32, 34]], [[20, 18, 42, 44]], [[1, 5, 29, 27]], [[13, 15, 39, 37]], [[6, 4, 28, 30]], [[16, 14, 38, 40]], [[0, 3, 25, 24]], [[9, 11, 35, 33]], [[19, 21, 45, 43]], [[12, 10, 34, 36]], [[22, 20, 44, 46]], [[5, 7, 31, 29]], [[15, 17, 41, 39]], [[2, 1, 27, 26]], [[8, 6, 30, 32]], [[18, 16, 40, 42]]]),
])
beam_13_placement = place(storey_placement, origin())
element("IfcBeam", 13, at=beam_13_placement, inside=storey, Name="diag", ObjectType="Viga", context=body_context, shape_type="Brep", body=[
    faceted_brep([(4.0666, 115.555, 5.8202), (4.6441, 115.555, 6.8469), (4.655, 115.5583, 6.8408), (4.0775, 115.5583, 5.8141), (4.0586, 115.5458, 5.8247), (4.6361, 115.5458, 6.8514), (4.0557, 115.5333, 5.8263), (4.6332, 115.5333, 6.8531), (4.0586, 115.5208, 5.8247), (4.6361, 115.5208, 6.8514), (4.0666, 115.5117, 5.8202), (4.6441, 115.5117, 6.8469), (4.0775, 115.5083, 5.8141), (4.655, 115.5083, 6.8408), (4.0884, 115.5117, 5.808), (4.6659, 115.5117, 6.8347), (4.0964, 115.5208, 5.8035), (4.6739, 115.5208, 6.8302), (4.0993, 115.5333, 5.8018), (4.6768, 115.5333, 6.8286), (4.0964, 115.5458, 5.8035), (4.6739, 115.5458, 6.8302), (4.0884, 115.555, 5.808), (4.6659, 115.555, 6.8347), (4.0756, 115.5371, 5.8151), (4.0775, 115.5376, 5.8141), (4.655, 115.5376, 6.8408), (4.6531, 115.5371, 6.8419), (4.0743, 115.5355, 5.8159), (4.6518, 115.5355, 6.8426), (4.0738, 115.5333, 5.8162), (4.6513, 115.5333, 6.8429), (4.0743, 115.5312, 5.8159), (4.6518, 115.5312, 6.8426), (4.0756, 115.5296, 5.8151), (4.6531, 115.5296, 6.8419), (4.0775, 115.529, 5.8141), (4.655, 115.529, 6.8408), (4.0794, 115.5296, 5.813), (4.6569, 115.5296, 6.8398), (4.0807, 115.5312, 5.8123), (4.6582, 115.5312, 6.839), (4.0812, 115.5333, 5.812), (4.6587, 115.5333, 6.8387), (4.0807, 115.5355, 5.8123), (4.6582, 115.5355, 6.839), (4.0794, 115.5371, 5.813), (4.6569, 115.5371, 6.8398)], [[[0, 1, 2, 3]], [[4, 5, 1, 0]], [[6, 7, 5, 4]], [[8, 9, 7, 6]], [[10, 11, 9, 8]], [[12, 13, 11, 10]], [[14, 15, 13, 12]], [[16, 17, 15, 14]], [[18, 19, 17, 16]], [[20, 21, 19, 18]], [[22, 23, 21, 20]], [[3, 2, 23, 22]], [[24, 25, 26, 27]], [[28, 24, 27, 29]], [[30, 28, 29, 31]], [[32, 30, 31, 33]], [[34, 32, 33, 35]], [[36, 34, 35, 37]], [[38, 36, 37, 39]], [[40, 38, 39, 41]], [[42, 40, 41, 43]], [[44, 42, 43, 45]], [[46, 44, 45, 47]], [[25, 46, 47, 26]], [[12, 10, 34, 36]], [[22, 20, 44, 46]], [[5, 7, 31, 29]], [[15, 17, 41, 39]], [[2, 1, 27, 26]], [[8, 6, 30, 32]], [[18, 16, 40, 42]], [[11, 13, 37, 35]], [[21, 23, 47, 45]], [[4, 0, 24, 28]], [[14, 12, 36, 38]], [[3, 22, 46, 25]], [[7, 9, 33, 31]], [[17, 19, 43, 41]], [[23, 2, 26, 47]], [[10, 8, 32, 34]], [[20, 18, 42, 44]], [[1, 5, 29, 27]], [[13, 15, 39, 37]], [[6, 4, 28, 30]], [[16, 14, 38, 40]], [[0, 3, 25, 24]], [[9, 11, 35, 33]], [[19, 21, 45, 43]]]),
])
beam_14_placement = place(storey_placement, origin())
element("IfcBeam", 14, at=beam_14_placement, inside=storey, Name="viga_long", ObjectType="Viga", context=body_context, shape_type="Brep", body=[
    faceted_brep([(3.35, 92.6, 5.7), (3.35, 127.0, 5.7), (3.65, 127.0, 5.7), (3.65, 92.6, 5.7), (3.35, 92.6, 6.0), (3.65, 92.6, 6.0), (3.65, 127.0, 6.0), (3.35, 127.0, 6.0)], [[[0, 1, 2, 3]], [[4, 5, 6, 7]], [[0, 3, 5, 4]], [[3, 2, 6, 5]], [[2, 1, 7, 6]], [[1, 0, 4, 7]]]),
])

save(model, "model.ifc")
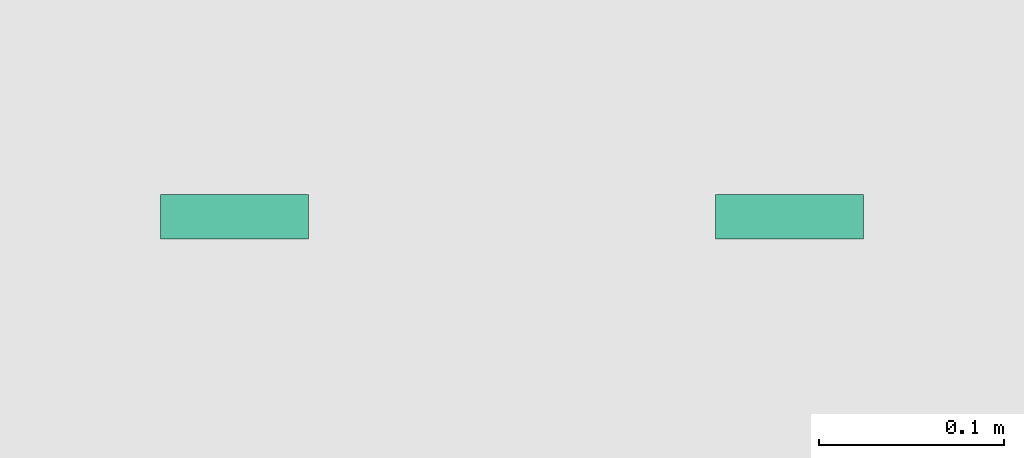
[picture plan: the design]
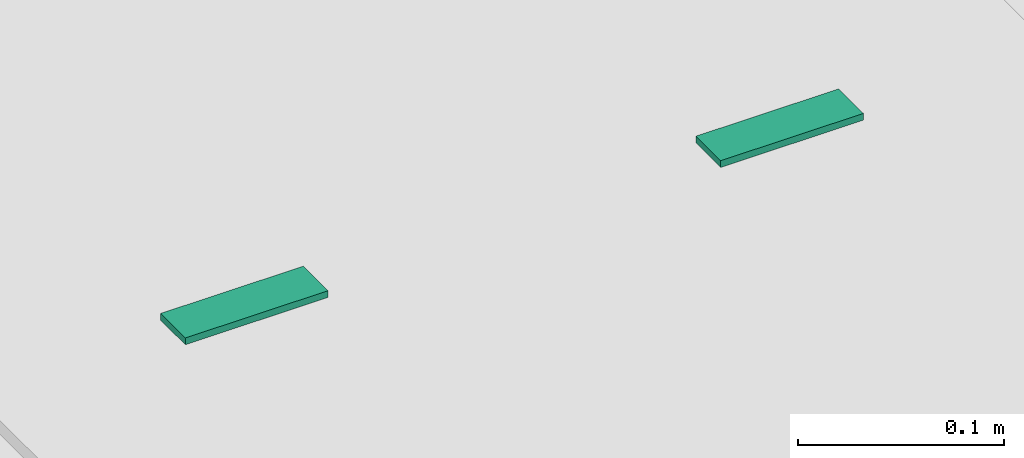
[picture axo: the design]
# One storey, part 134 of 166: 2 distribution chamber elements.
"""IFC2X3 building model written with IfcOpenShell, lengths in metres."""

from ifc_helpers import new_model, si_unit, origin, origin_with_axes, place, context, subcontext, project, spatial, faceted_brep, element, save


model = new_model("IFC2X3")

# Units and contexts
model_context = context("Model", 3, precision=1e-05, world=origin_with_axes())
body_context = subcontext(model_context, "Body", "Model", "MODEL_VIEW")
ifc_project = project(units=[si_unit("LENGTHUNIT", "METRE"), si_unit("AREAUNIT", "SQUARE_METRE"), si_unit("VOLUMEUNIT", "CUBIC_METRE"), si_unit("PLANEANGLEUNIT", "RADIAN")], contexts=[model_context])

# Site, building, storey
site_placement = place(None, origin_with_axes())
site = spatial("IfcSite", under=ifc_project, at=site_placement, CompositionType="ELEMENT")
building_placement = place(site_placement, origin())
building = spatial("IfcBuilding", under=site, at=building_placement, Name="de Temporal", CompositionType="ELEMENT")
storey_placement = place(building_placement, origin())
storey = spatial("IfcBuildingStorey", under=building, at=storey_placement, Name="NIVEL 1 (NPT +0.00)", CompositionType="ELEMENT", Elevation=0.0)

# Distribution chamber elements
distribution_chamber_element_1_placement = place(storey_placement, origin())
element("IfcDistributionChamberElement", 1, at=distribution_chamber_element_1_placement, inside=storey, ObjectType="de", context=body_context, shape_type="Brep", body=[
    faceted_brep([(65.402, 88.317, 0.104), (65.402, 88.341, 0.104), (65.482, 88.341, 0.104), (65.482, 88.317, 0.104), (65.402, 88.317, 0.108), (65.482, 88.317, 0.108), (65.482, 88.341, 0.108), (65.402, 88.341, 0.108)], [[[0, 1, 2, 3]], [[4, 5, 6, 7]], [[0, 3, 5, 4]], [[3, 2, 6, 5]], [[2, 1, 7, 6]], [[1, 0, 4, 7]]]),
])
distribution_chamber_element_2_placement = place(storey_placement, origin())
element("IfcDistributionChamberElement", 2, at=distribution_chamber_element_2_placement, inside=storey, ObjectType="de", context=body_context, shape_type="Brep", body=[
    faceted_brep([(65.702, 88.317, 0.104), (65.702, 88.341, 0.104), (65.782, 88.341, 0.104), (65.782, 88.317, 0.104), (65.702, 88.317, 0.108), (65.782, 88.317, 0.108), (65.782, 88.341, 0.108), (65.702, 88.341, 0.108)], [[[0, 1, 2, 3]], [[4, 5, 6, 7]], [[0, 3, 5, 4]], [[3, 2, 6, 5]], [[2, 1, 7, 6]], [[1, 0, 4, 7]]]),
])

save(model, "model.ifc")
